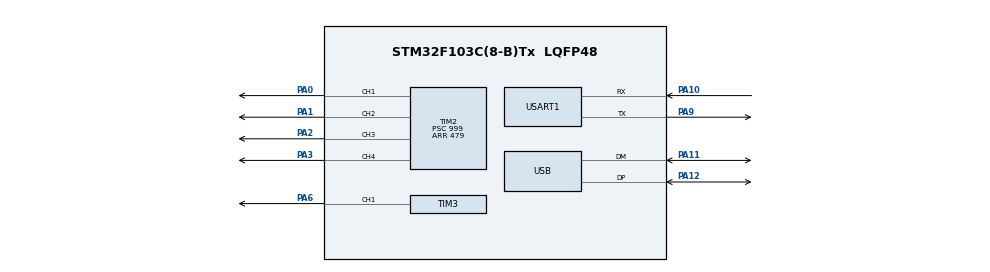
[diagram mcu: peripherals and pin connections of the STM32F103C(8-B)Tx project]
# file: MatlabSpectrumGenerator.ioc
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Mcu.Family=STM32F1
Mcu.Name=STM32F103C(8-B)Tx
Mcu.Package=LQFP48
NVIC.PriorityGroup=NVIC_PRIORITYGROUP_4
NVIC.USART1_IRQn=true\:0\:0\:false\:false\:true\:true
NVIC.USB_LP_CAN1_RX0_IRQn=true\:0\:0\:false\:false\:true\:false
PA0-WKUP.Signal=S_TIM2_CH1_ETR
PA1.Signal=S_TIM2_CH2
PA10.Mode=Asynchronous
PA10.Signal=USART1_RX
PA11.Mode=Device
PA11.Signal=USB_DM
PA12.Mode=Device
PA12.Signal=USB_DP
PA13.Mode=Serial_Wire
PA13.Signal=SYS_JTMS-SWDIO
PA14.Mode=Serial_Wire
PA14.Signal=SYS_JTCK-SWCLK
PA2.Signal=S_TIM2_CH3
PA3.Signal=S_TIM2_CH4
PA6.Signal=S_TIM3_CH1
PA9.Mode=Asynchronous
PA9.Signal=USART1_TX
PD0-OSC_IN.Mode=HSE-External-Oscillator
PD0-OSC_IN.Signal=RCC_OSC_IN
PD1-OSC_OUT.Mode=HSE-External-Oscillator
PD1-OSC_OUT.Signal=RCC_OSC_OUT
ProjectManager.HeapSize=0x200
ProjectManager.StackSize=0x400
ProjectManager.TargetToolchain=TrueSTUDIO
RCC.AHBFreq_Value=48000000
RCC.APB1CLKDivider=RCC_HCLK_DIV2
RCC.APB1Freq_Value=24000000
RCC.APB1TimFreq_Value=48000000
RCC.APB2Freq_Value=48000000
RCC.APB2TimFreq_Value=48000000
RCC.HCLKFreq_Value=48000000
RCC.PLLMUL=RCC_PLL_MUL6
RCC.SYSCLKFreq_VALUE=48000000
RCC.SYSCLKSource=RCC_SYSCLKSOURCE_PLLCLK
RCC.USBFreq_Value=48000000
SH.S_TIM2_CH1_ETR.0=TIM2_CH1,PWM Generation1 CH1
SH.S_TIM2_CH2.0=TIM2_CH2,PWM Generation2 CH2
SH.S_TIM2_CH3.0=TIM2_CH3,PWM Generation3 CH3
SH.S_TIM2_CH4.0=TIM2_CH4,PWM Generation4 CH4
SH.S_TIM3_CH1.0=TIM3_CH1,PWM Generation1 CH1
TIM2.Channel-PWM\ Generation1\ CH1=TIM_CHANNEL_1
TIM2.Channel-PWM\ Generation2\ CH2=TIM_CHANNEL_2
TIM2.Channel-PWM\ Generation3\ CH3=TIM_CHANNEL_3
TIM2.Channel-PWM\ Generation4\ CH4=TIM_CHANNEL_4
TIM2.Period=479
TIM2.Prescaler=999
TIM2.Pulse-PWM\ Generation1\ CH1=239
TIM2.Pulse-PWM\ Generation2\ CH2=239
TIM2.Pulse-PWM\ Generation3\ CH3=239
TIM2.Pulse-PWM\ Generation4\ CH4=239
TIM3.Channel-PWM\ Generation1\ CH1=TIM_CHANNEL_1
TIM3.Period=479
TIM3.Prescaler=999
TIM3.Pulse-PWM\ Generation1\ CH1=239
USART1.VirtualMode=VM_ASYNC
USB_DEVICE.CLASS_NAME_FS=CUSTOMHID
USB_DEVICE.USBD_CUSTOMHID_OUTREPORT_BUF_SIZE=8
USB_DEVICE.USBD_CUSTOM_HID_REPORT_DESC_SIZE=38
USB_DEVICE.VirtualMode=CustomHid
USB_DEVICE.VirtualModeFS=Custom_Hid_FS
VP_TIM2_VS_ClockSourceINT.Mode=Internal
VP_TIM3_VS_ClockSourceINT.Mode=Internal
VP_USB_DEVICE_VS_USB_DEVICE_CUSTOM_HID_FS.Mode=CUSTOM_HID_FS
board=MatlabSpectrumGenerator

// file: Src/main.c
/**
  ******************************************************************************
  * @file           : main.c
  * @brief          : Main program body
  ******************************************************************************
  * This notice applies to any and all portions of this file
  * that are not between comment pairs USER CODE BEGIN and
  * USER CODE END. Other portions of this file, whether
  * inserted by the user or by software development tools
  * are owned by their respective copyright owners.
  *
  * Copyright (c) 2018 STMicroelectronics International N.V.
  * All rights reserved.
  *
  * Redistribution and use in source and binary forms, with or without
  * modification, are permitted, provided that the following conditions are met:
  *
  * 1. Redistribution of source code must retain the above copyright notice,
  *    this list of conditions and the following disclaimer.
  * 2. Redistributions in binary form must reproduce the above copyright notice,
  *    this list of conditions and the following disclaimer in the documentation
  *    and/or other materials provided with the distribution.
  * 3. Neither the name of STMicroelectronics nor the names of other
  *    contributors to this software may be used to endorse or promote products
  *    derived from this software without specific written permission.
  * 4. This software, including modifications and/or derivative works of this
  *    software, must execute solely and exclusively on microcontroller or
  *    microprocessor devices manufactured by or for STMicroelectronics.
  * 5. Redistribution and use of this software other than as permitted under
  *    this license is void and will automatically terminate your rights under
  *    this license.
  *
  * THIS SOFTWARE IS PROVIDED BY STMICROELECTRONICS AND CONTRIBUTORS "AS IS"
  * AND ANY EXPRESS, IMPLIED OR STATUTORY WARRANTIES, INCLUDING, BUT NOT
  * LIMITED TO, THE IMPLIED WARRANTIES OF MERCHANTABILITY, FITNESS FOR A
  * PARTICULAR PURPOSE AND NON-INFRINGEMENT OF THIRD PARTY INTELLECTUAL PROPERTY
  * RIGHTS ARE DISCLAIMED TO THE FULLEST EXTENT PERMITTED BY LAW. IN NO EVENT
  * SHALL STMICROELECTRONICS OR CONTRIBUTORS BE LIABLE FOR ANY DIRECT, INDIRECT,
  * INCIDENTAL, SPECIAL, EXEMPLARY, OR CONSEQUENTIAL DAMAGES (INCLUDING, BUT NOT
  * LIMITED TO, PROCUREMENT OF SUBSTITUTE GOODS OR SERVICES; LOSS OF USE, DATA,
  * OR PROFITS; OR BUSINESS INTERRUPTION) HOWEVER CAUSED AND ON ANY THEORY OF
  * LIABILITY, WHETHER IN CONTRACT, STRICT LIABILITY, OR TORT (INCLUDING
  * NEGLIGENCE OR OTHERWISE) ARISING IN ANY WAY OUT OF THE USE OF THIS SOFTWARE,
  * EVEN IF ADVISED OF THE POSSIBILITY OF SUCH DAMAGE.
  *
  ******************************************************************************
  */
#include "main.h"
#include "stm32f1xx_hal.h"
#include "tim.h"
#include "usart.h"
#include "usb_device.h"
#include "gpio.h"

/* USER CODE BEGIN Includes */
#include "usbd_customhid.h"
/* USER CODE END Includes */

/* USER CODE BEGIN PV */
/* Private variables ---------------------------------------------------------*/
extern USBD_HandleTypeDef hUsbDeviceFS;
extern TIM_HandleTypeDef htim2;
extern TIM_HandleTypeDef htim3;
/* USER CODE END PV */

void SystemClock_Config(void);

/* USER CODE BEGIN PFP */
/* Private function prototypes -----------------------------------------------*/

/* USER CODE END PFP */

/* USER CODE BEGIN 0 */
void HandleUSB(char * USB_String, int String_Length)
{
	if (strncmp(USB_String,"PD",2)==0)
	{
		USBD_CUSTOM_HID_SendReport(&hUsbDeviceFS,(uint8_t *)USB_String, String_Length);
		int PD_NUMBER = ((int)USB_String[2] - (int)'1' + 1);
		int PWM = atoi(&USB_String[4]);
		switch(PD_NUMBER)
		{
			case 1:
				__HAL_TIM_SET_COMPARE(&htim2, TIM_CHANNEL_1, PWM-1);
				break;
			case 2:
				__HAL_TIM_SET_COMPARE(&htim2, TIM_CHANNEL_2, PWM-1);
				break;
			case 3:
				__HAL_TIM_SET_COMPARE(&htim2, TIM_CHANNEL_3, PWM-1);
				break;
			case 4:
				__HAL_TIM_SET_COMPARE(&htim2, TIM_CHANNEL_4, PWM-1);
				break;
			case 5:
				__HAL_TIM_SET_COMPARE(&htim3, TIM_CHANNEL_1, PWM-1);
				break;
		}
	}
	else HAL_UART_Transmit(&huart1, (uint8_t*)USB_String, String_Length, 1);
}

void HandleUARTCommand(char * CMD_String, int String_Length)
{
	USBD_CUSTOM_HID_SendReport(&hUsbDeviceFS,(uint8_t *)CMD_String, String_Length);
}
/* USER CODE END 0 */

int main(void)
{

  /* MCU Configuration----------------------------------------------------------*/

  /* Reset of all peripherals, Initializes the Flash interface and the Systick. */
  HAL_Init();

  /* Configure the system clock */
  SystemClock_Config();

  /* Initialize all configured peripherals */
  MX_GPIO_Init();
  MX_USB_DEVICE_Init();
  MX_USART1_UART_Init();
  MX_TIM2_Init();
  MX_TIM3_Init();
  /* USER CODE BEGIN 2 */
  __HAL_UART_ENABLE_IT(&huart1, UART_IT_RXNE);
  HAL_TIM_PWM_Start(&htim2, TIM_CHANNEL_1);
  HAL_TIM_PWM_Start(&htim2, TIM_CHANNEL_2);
  HAL_TIM_PWM_Start(&htim2, TIM_CHANNEL_3);
  HAL_TIM_PWM_Start(&htim2, TIM_CHANNEL_4);
  HAL_TIM_PWM_Start(&htim3, TIM_CHANNEL_1);
  /* USER CODE END 2 */

  /* Infinite loop */
  while (1)
  {

  }

}

void SystemClock_Config(void)
{

  RCC_OscInitTypeDef RCC_OscInitStruct;
  RCC_ClkInitTypeDef RCC_ClkInitStruct;
  RCC_PeriphCLKInitTypeDef PeriphClkInit;

    /**Initializes the CPU, AHB and APB busses clocks
    */
  RCC_OscInitStruct.OscillatorType = RCC_OSCILLATORTYPE_HSE;
  RCC_OscInitStruct.HSEState = RCC_HSE_ON;
  RCC_OscInitStruct.HSEPredivValue = RCC_HSE_PREDIV_DIV1;
  RCC_OscInitStruct.HSIState = RCC_HSI_ON;
  RCC_OscInitStruct.PLL.PLLState = RCC_PLL_ON;
  RCC_OscInitStruct.PLL.PLLSource = RCC_PLLSOURCE_HSE;
  RCC_OscInitStruct.PLL.PLLMUL = RCC_PLL_MUL3;
  if (HAL_RCC_OscConfig(&RCC_OscInitStruct) != HAL_OK)
  {
    _Error_Handler(__FILE__, __LINE__);
  }

    /**Initializes the CPU, AHB and APB busses clocks
    */
  RCC_ClkInitStruct.ClockType = RCC_CLOCKTYPE_HCLK|RCC_CLOCKTYPE_SYSCLK
                              |RCC_CLOCKTYPE_PCLK1|RCC_CLOCKTYPE_PCLK2;
  RCC_ClkInitStruct.SYSCLKSource = RCC_SYSCLKSOURCE_PLLCLK;
  RCC_ClkInitStruct.AHBCLKDivider = RCC_SYSCLK_DIV1;
  RCC_ClkInitStruct.APB1CLKDivider = RCC_HCLK_DIV2;
  RCC_ClkInitStruct.APB2CLKDivider = RCC_HCLK_DIV1;

  if (HAL_RCC_ClockConfig(&RCC_ClkInitStruct, FLASH_LATENCY_1) != HAL_OK)
  {
    _Error_Handler(__FILE__, __LINE__);
  }

  PeriphClkInit.PeriphClockSelection = RCC_PERIPHCLK_USB;
  PeriphClkInit.UsbClockSelection = RCC_USBCLKSOURCE_PLL;
  if (HAL_RCCEx_PeriphCLKConfig(&PeriphClkInit) != HAL_OK)
  {
    _Error_Handler(__FILE__, __LINE__);
  }

    /**Configure the Systick interrupt time
    */
  HAL_SYSTICK_Config(HAL_RCC_GetHCLKFreq()/1000);

    /**Configure the Systick
    */
  HAL_SYSTICK_CLKSourceConfig(SYSTICK_CLKSOURCE_HCLK);

  /* SysTick_IRQn interrupt configuration */
  HAL_NVIC_SetPriority(SysTick_IRQn, 0, 0);
}

void _Error_Handler(char *file, int line)
{
  while(1)
  {
  }
}

/************************ (C) COPYRIGHT STMicroelectronics *****END OF FILE****/
